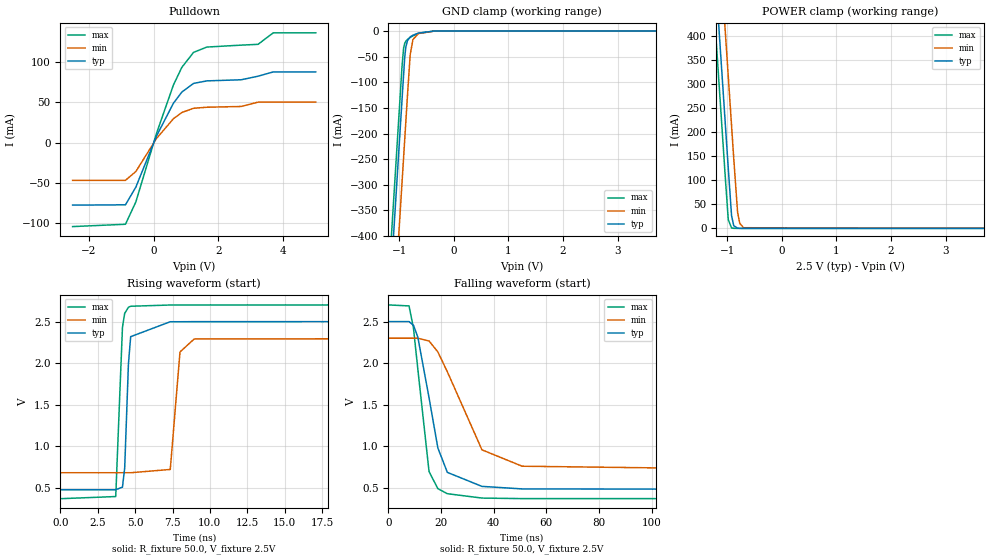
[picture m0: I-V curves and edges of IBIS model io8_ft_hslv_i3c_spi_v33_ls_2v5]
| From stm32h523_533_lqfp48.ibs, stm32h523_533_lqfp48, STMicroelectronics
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[Model]   io8_ft_hslv_i3c_spi_v33_ls_2v5
Model_type I/O_open_drain
Polarity   Non-Inverting
Enable   Active-Low
| CAP_THRESHOLD on pad IOFT is "UDTCAPC" :
| Rising=20.0% of vddiom   Falling=80.0% of vddiom
| C_comp min and max val. don't necessarily correlate with the min and max pvt
| but are the smallest and greatest pad capacitance found.
| var   typ   min   max
C_comp   3.86836pF  3.83545pF  3.96274pF
|C_comp_pulldown   3.86836pF  3.83545pF  3.96274pF
Vinl = 1.15V
Vinh = 1.35V
Vmeas = 1.25V   | Reference voltage for timing measurements
Cref  = 50.0pF   | Timing specification test load capacitance value
Rref  = 1.0MOhm   | Timing specification test load resistance value
Vref  = 1.375V   | Timing specification test load voltage
[Model Spec]
| TIME_THRESHOLD on pin ZII2CV11 is "CMOS" :
| Rising=40.0% of vdd   Falling=60.0% of vdd
Vinl 978.80000mV 906.80000mV 1.05480V
Vinh 1.39920V 1.29220V 1.48720V
| variable   typ   min   max
[Temperature Range] 25.0 125.0 -40.0
| variable   typ   min   max
[Voltage Range] 2.5V 2.3V 2.7V
| variable   typ   min   max
[POWER Clamp Reference] 2.5V 2.3V 2.7V
| variable   typ   min   max
[GND Clamp Reference] 0V 0V 0V
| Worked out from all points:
|   slope of the pulldown table from 0 to 0.375 V, typ, clamps not added: 11.5 ohm
|   GND clamp passes 1 mA (typ) near -0.52 V on its own axis
|   POWER clamp passes 1 mA (typ) near -0.84 V on its own axis
|   rising waveform, R_fixture 50.0, V_fixture 2.5V: 20-80 % time 253ps typ, 304ps min, 242ps max; typ from 0.481 V to 2.5 V
|   falling waveform, R_fixture 50.0, V_fixture 2.5V: 20-80 % time 6.98ns typ, 13.1ns min, 4.56ns max; typ from 2.5 V to 0.481 V
[POWER Clamp]
-2.5V     2.708A     2.899A     2.597A
-1.23V    548.8mA    740.2mA    437.5mA
-1.16V    429.8mA    621.2mA    318.5mA
-1.12V    361.8mA    553.2mA    250.5mA
-1.03V    208.8mA    400.2mA    97.53mA
-980mV    123.8mA    315.2mA    17.95mA
-920mV    26.3mA     213.2mA    906uA
-880mV    5.543mA    145.2mA    123.7uA
-810mV    363.5uA    33.6mA     3.797uA
-770mV    76.62uA    10.47mA    518.8nA
-700mV    5.026uA    1.361mA    16.09nA
5V        0A         0A         0A
[GND Clamp]
-2.5V     -2.77A     -2.931A    -2.704A
-1.21V    -576.8mA   -738.1mA   -511.3mA
-950mV    -134.8mA   -296.1mA   -69.34mA
-920mV    -83.82mA   -245.1mA   -32.48mA
-900mV    -50.56mA   -211.1mA   -24.02mA
-880mV    -31.31mA   -177.1mA   -19.85mA
-850mV    -18.7mA    -126.1mA   -16.34mA
-800mV    -11.46mA   -46.18mA   -12.45mA
-750mV    -8.203mA   -16.63mA   -9.325mA
-650mV    -4.063mA   -4.987mA   -4.427mA
-360mV    -35.05uA   -165.1uA   -9.564uA
5V        7.96nA     1.281uA    294pA
| variable   typ   min   max
[Pullup Reference] 2.5V 2.3V 2.7V
| variable   typ   min   max
[Pulldown Reference] 0V 0V 0V
[Pulldown]
-2.5V     -77.63mA   -46.85mA   -104.3mA
-870mV    -77.24mA   -46.85mA   -101.4mA
-550mV    -55.3mA    -35.88mA   -73.72mA
90mV      8.401mA    5.299mA    11.79mA
610mV     49.03mA    29.75mA    71.69mA
870mV     62.92mA    37.48mA    93.62mA
1.23V     73.63mA    42.72mA    112.2mA
1.64V     76.78mA    44.01mA    118.8mA
2.7V      78.15mA    44.99mA    121.2mA
3.22V     82.58mA    50.35mA    122.2mA
3.69V     87.93mA    50.35mA    136.5mA
5V        87.93mA    50.35mA    136.5mA
[Ramp]
dV/dt_r 1.21163V/248.65431ps 969.22844mV/300.79995ps 1.39627V/238.26042ps
dV/dt_f 1.21165V/6.77947ns 969.25319mV/12.8558ns 1.39628V/4.50807ns
R_load = 50.0
| Removed startup time: 0s 0s 0s  .
| Removed end time: 48.75ns.
[Rising Waveform]
R_fixture   = 50.0
V_fixture   = 2.5V
V_fixture_min = 2.3V
V_fixture_max = 2.7V
0s        480.6mV    684.6mV    372.9mV
3.7ns     480.3mV    684.6mV    398.7mV
4.15ns    511.7mV    684.6mV    2.431V
4.3ns     743.3mV    684.6mV    2.599V
4.55ns    1.992V     684.6mV    2.672V
4.7ns     2.319V     684.6mV    2.684V
7.35ns    2.498V     724.2mV    2.699V
8ns       2.498V     2.135V     2.699V
8.95ns    2.499V     2.291V     2.7V
48.75ns   2.5V       2.3V       2.7V
| Removed startup time: 0s 0s 0s  .
| Removed end time: 248.75ns.
[Falling Waveform]
R_fixture   = 50.0
V_fixture   = 2.5V
V_fixture_min = 2.3V
V_fixture_max = 2.7V
0s        2.5V       2.3V       2.7V
7.85ns    2.5V       2.3V       2.688V
9.55ns    2.455V     2.3V       2.418V
11.2ns    2.312V     2.3V       1.927V
15.45ns   1.586V     2.267V     699mV
18.8ns    982.2mV    2.136V     493.4mV
22.4ns    689mV      1.897V     433mV
35.55ns   520.7mV    959.9mV    380.4mV
50.8ns    490.4mV    763mV      373.9mV
248.8ns   480.6mV    684.6mV    372.9mV
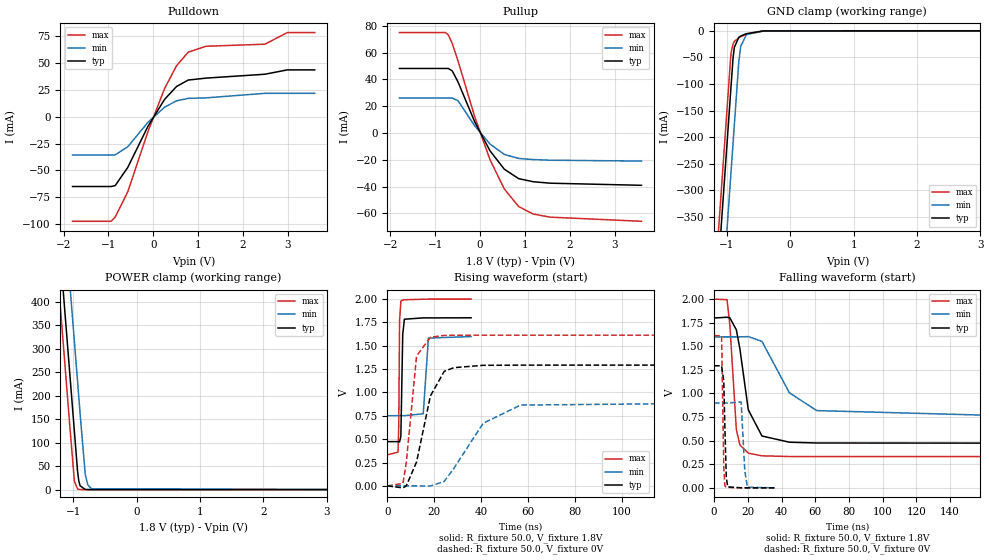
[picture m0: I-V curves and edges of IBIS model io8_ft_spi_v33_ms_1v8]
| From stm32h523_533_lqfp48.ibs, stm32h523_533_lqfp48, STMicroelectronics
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[Model]   io8_ft_spi_v33_ms_1v8
Model_type I/O
Polarity   Non-Inverting
Enable   Active-Low
| CAP_THRESHOLD on pad IOFT is "UDTCAPC" :
| Rising=20.0% of vddiom   Falling=80.0% of vddiom
| C_comp min and max val. don't necessarily correlate with the min and max pvt
| but are the smallest and greatest pad capacitance found.
| var   typ   min   max
C_comp   3.69208pF  3.66965pF  3.86716pF
|C_comp_pullup   2.28990pF  2.21760pF  2.21555pF
|C_comp_pulldown   1.40218pF  1.45205pF  1.65161pF
Vinl = 480.0mV
Vinh = 1.4V
Vmeas = 900.0mV   | Reference voltage for timing measurements
Cref  = 50.0pF   | Timing specification test load capacitance value
Rref  = 100.0MOhm   | Timing specification test load resistance value
Vref  = 900.0mV   | Timing specification test load voltage
[Model Spec]
| TIME_THRESHOLD on pin ZIV33M is "CMOS" :
| Rising=40.0% of vddiom   Falling=60.0% of vddiom
Vinl 693.80000mV 621.80000mV 774.80000mV
Vinh 1.05820V 933.20000mV 1.16320V
| variable   typ   min   max
[Temperature Range] 25.0 125.0 -40.0
| variable   typ   min   max
[Voltage Range] 1.8V 1.6V 2.0V
| variable   typ   min   max
[POWER Clamp Reference] 1.8V 1.6V 2.0V
| variable   typ   min   max
[GND Clamp Reference] 0V 0V 0V
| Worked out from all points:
|   slope of the pulldown table from 0 to 0.27 V, typ, clamps not added: 15.8 ohm
|   slope of the pullup table from 0 to 0.27 V, typ, clamps not added: 17.1 ohm
|   GND clamp passes 1 mA (typ) near -0.52 V on its own axis
|   POWER clamp passes 1 mA (typ) near -0.84 V on its own axis
|   rising waveform, R_fixture 50.0, V_fixture 1.8V: 20-80 % time 414ps typ, 848ps min, 290ps max; typ from 0.474 V to 1.8 V
|   falling waveform, R_fixture 50.0, V_fixture 1.8V: 20-80 % time 7.23ns typ, 16.4ns min, 3.35ns max; typ from 1.8 V to 0.474 V
|   rising waveform, R_fixture 50.0, V_fixture 0V: 20-80 % time 6.85ns typ, 15ns min, 3.49ns max; typ from 0 V to 1.29 V
|   falling waveform, R_fixture 50.0, V_fixture 0V: 20-80 % time 1.1ns typ, 1.58ns min, 753ps max; typ from 1.29 V to 0 V
[POWER Clamp]
-1.8V     1.518A     1.709A     1.407A
-1.23V    548.8mA    740.2mA    437.5mA
-1.16V    429.8mA    621.2mA    318.5mA
-1.05V    242.8mA    434.2mA    131.5mA
-980mV    123.8mA    315.2mA    17.95mA
-930mV    38.81mA    230.2mA    1.49mA
-910mV    17.82mA    196.2mA    550.8uA
-890mV    8.18mA     162.2mA    203.5uA
-810mV    363.5uA    33.6mA     3.797uA
-770mV    76.62uA    10.47mA    518.8nA
-710mV    7.416uA    1.822mA    26.34nA
3.6V      0A         0A         0A
[GND Clamp]
-1.8V     -1.579A    -1.74A     -1.515A
-1.24V    -627.3mA   -788.3mA   -562.7mA
-1.05V    -304.3mA   -465.3mA   -239.7mA
-940mV    -117.3mA   -278.3mA   -52.69mA
-930mV    -100.3mA   -261.3mA   -40.52mA
-900mV    -50.11mA   -210.3mA   -24.23mA
-880mV    -30.95mA   -176.3mA   -20.02mA
-810mV    -12.18mA   -57.97mA   -13.23mA
-780mV    -9.807mA   -29.1mA    -11.19mA
-690mV    -5.41mA    -7.142mA   -6.184mA
-420mV    -170.4uA   -446.1uA   -81.94uA
3.6V      5.755nA    953.4nA    228.2pA
| variable   typ   min   max
[Pullup Reference] 1.8V 1.6V 2.0V
| variable   typ   min   max
[Pulldown Reference] 0V 0V 0V
[Pullup]
-1.8V     48.22mA    26.13mA    75.02mA
-770mV    48.22mA    26.13mA    75.02mA
-710mV    48.22mA    26.13mA    73.25mA
-620mV    46.37mA    26.13mA    66.82mA
-490mV    37.97mA    24.09mA    53.59mA
-120mV    8.372mA    5.391mA    12.2mA
220mV     -13.2mA    -8.17mA    -19.85mA
540mV     -27mA      -15.96mA   -41.75mA
860mV     -34.04mA   -18.97mA   -54.88mA
1.18V     -36.34mA   -19.79mA   -60.45mA
1.56V     -37.44mA   -20.28mA   -62.79mA
3.6V      -39.03mA   -20.93mA   -65.9mA
[Pulldown]
-1.8V     -65.02mA   -35.56mA   -97.42mA
-940mV    -65.02mA   -35.56mA   -97.42mA
-850mV    -64.17mA   -35.56mA   -93.49mA
-570mV    -47.32mA   -28.01mA   -70.04mA
-120mV    -9.088mA   -5.279mA   -14.07mA
250mV     16.04mA    8.832mA    26.05mA
520mV     28.19mA    14.82mA    47.53mA
780mV     34.17mA    17.07mA    60.14mA
1.18V     35.97mA    17.56mA    65.65mA
2.49V     39.57mA    21.77mA    67.55mA
2.99V     43.62mA    21.77mA    78.38mA
3.6V      43.62mA    21.77mA    78.38mA
[Ramp]
dV/dt_r 776.15149mV/6.73951ns 539.49296mV/14.79132ns 968.54289mV/3.48709ns
dV/dt_f 795.78722mV/6.62356ns 508.97361mV/16.22716ns 1.00099V/3.34756ns
R_load = 50.0
| Removed startup time: 0s 0s 0s  .
| Removed end time: 35.75ns.
[Rising Waveform]
R_fixture   = 50.0
V_fixture   = 1.8V
V_fixture_min = 1.6V
V_fixture_max = 2.0V
0s        473.7mV    751.7mV    331.7mV
4.6ns     473.7mV    751.7mV    361.3mV
4.9ns     472.5mV    751.7mV    645.3mV
5.25ns    470.5mV    751.7mV    1.766V
5.8ns     531mV      751.7mV    1.979V
6.6ns     1.624V     751.7mV    1.991V
7.3ns     1.785V     751.7mV    1.993V
15.35ns   1.799V     772mV      1.999V
17.55ns   1.799V     1.583V     2V
35.75ns   1.8V       1.599V     2V
| Removed startup time: 0s 0s 0s  .
| Removed end time: 198.75ns.
[Falling Waveform]
R_fixture   = 50.0
V_fixture   = 1.8V
V_fixture_min = 1.6V
V_fixture_max = 2.0V
0s        1.8V       1.6V       2V
7.7ns     1.808V     1.6V       1.994V
9.4ns     1.8V       1.6V       1.717V
13.2ns    1.675V     1.6V       619.4mV
15.3ns    1.475V     1.6V       455.6mV
20.3ns    827.5mV    1.603V     367.9mV
28.4ns    549.5mV    1.552V     339.5mV
44.65ns   483.9mV    1.008V     332.2mV
60.85ns   475.4mV    818.9mV    331.7mV
198.8ns   473.7mV    751.7mV    331.7mV
| Removed startup time: 0s 0s 0s  .
| Removed end time: 198.6ns.
[Rising Waveform]
R_fixture   = 50.0
V_fixture   = 0V
V_fixture_min = 0V
V_fixture_max = 0V
0s        178.4nV    440.5nV    128.9nV
6.7ns     -21.42mV   449.7nV    26.51mV
8.1ns     -968.5uV   454.4nV    244.7mV
12.5ns    256.2mV    -1.06uV    1.391V
18.4ns    962.8mV    -1.644mV   1.592V
24.3ns    1.227V     47.4mV     1.611V
28.4ns    1.266V     187.6mV    1.613V
40.9ns    1.291V     670.2mV    1.614V
56.8ns    1.293V     864.8mV    1.614V
198.6ns   1.294V     899.2mV    1.614V
| Removed startup time: 0s 0s 0s  .
| Removed end time: 35.75ns.
[Falling Waveform]
R_fixture   = 50.0
V_fixture   = 0V
V_fixture_min = 0V
V_fixture_max = 0V
0s        1.294V     899.3mV    1.614V
4.45ns    1.293V     899.3mV    1.612V
5.75ns    1.134V     899.3mV    218.7mV
6.4ns     642.4mV    899.3mV    21.23mV
7.25ns    117.6mV    899.3mV    5.199mV
8.05ns    10.65mV    899.3mV    4.431mV
16.05ns   846.3uV    909.9mV    359.1uV
18.25ns   570.8uV    174.5mV    248.1uV
19.75ns   461.9uV    7.352mV    194.3uV
35.75ns   73.53uV    645.7uV    14.1uV
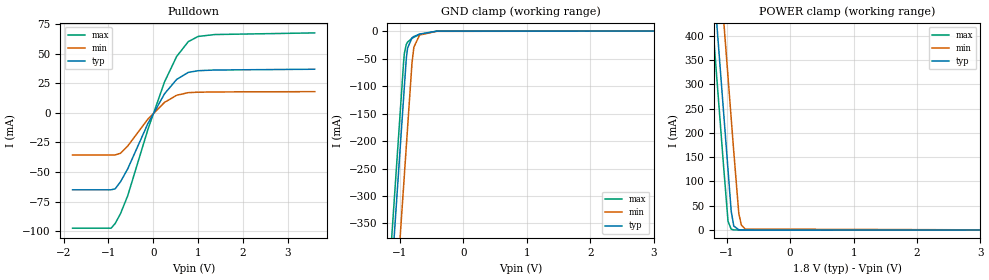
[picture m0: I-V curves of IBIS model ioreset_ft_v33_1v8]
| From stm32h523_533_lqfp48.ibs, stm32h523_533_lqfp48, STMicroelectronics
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[Model]   ioreset_ft_v33_1v8
Model_type I/O_open_drain
Polarity   Inverting
Enable   Active-Low
| CAP_THRESHOLD on pad IOFT is "UDTCAPC" :
| Rising=20.0% of vddiom   Falling=80.0% of vddiom
| C_comp min and max val. don't necessarily correlate with the min and max pvt
| but are the smallest and greatest pad capacitance found.
| var   typ   min   max
C_comp   3.16940pF  3.14035pF  3.18100pF
|C_comp_pulldown   3.16940pF  3.14035pF  3.18100pF
Vinl = 800.0mV
Vinh = 1.0V
Vmeas = 900.0mV   | Reference voltage for timing measurements
Cref  = 50.0pF   | Timing specification test load capacitance value
Rref  = 1.0MOhm   | Timing specification test load resistance value
Vref  = 990.0mV   | Timing specification test load voltage
[Model Spec]
| TIME_THRESHOLD on pin ZIV33M is "CMOS" :
| Rising=40.0% of vddiom   Falling=60.0% of vddiom
Vinl 699.80000mV 627.80000mV 779.80000mV
Vinh 1.05220V 928.20000mV 1.15620V
| variable   typ   min   max
[Temperature Range] 25.0 125.0 -40.0
| variable   typ   min   max
[Voltage Range] 1.8V 1.6V 2.0V
| variable   typ   min   max
[POWER Clamp Reference] 1.8V 1.6V 2.0V
| variable   typ   min   max
[GND Clamp Reference] 0V 0V 0V
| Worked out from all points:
|   slope of the pulldown table from 0 to 0.27 V, typ, clamps not added: 15.8 ohm
|   GND clamp passes 1 mA (typ) near -0.52 V on its own axis
|   POWER clamp passes 1 mA (typ) near -0.84 V on its own axis
[POWER Clamp]
-1.8V     1.518A     1.709A     1.407A
-1.24V    565.8mA    757.2mA    454.5mA
-1.18V    463.8mA    655.2mA    352.5mA
-1.11V    344.8mA    536.2mA    233.5mA
-1.05V    242.8mA    434.2mA    131.5mA
-980mV    123.8mA    315.2mA    17.95mA
-930mV    38.81mA    230.2mA    1.49mA
-890mV    8.18mA     162.2mA    203.5uA
-810mV    363.5uA    33.6mA     3.797uA
-770mV    76.62uA    10.47mA    518.7nA
-710mV    7.416uA    1.822mA    26.23nA
3.6V      0A         0A         0A
[GND Clamp]
-1.8V     -1.579A    -1.74A     -1.515A
-1.24V    -627.3mA   -788.3mA   -562.7mA
-1.05V    -304.3mA   -465.3mA   -239.7mA
-940mV    -117.3mA   -278.3mA   -52.69mA
-930mV    -100.3mA   -261.3mA   -40.52mA
-900mV    -50.11mA   -210.3mA   -24.22mA
-880mV    -30.95mA   -176.3mA   -20.02mA
-810mV    -12.18mA   -57.96mA   -13.22mA
-780mV    -9.803mA   -29.1mA    -11.18mA
-690mV    -5.404mA   -7.14mA    -6.176mA
-420mV    -168.9uA   -443.8uA   -80.87uA
3.6V      312.6pA    43.66nA    94.46pA
| variable   typ   min   max
[Pullup Reference] 1.8V 1.6V 2.0V
| variable   typ   min   max
[Pulldown Reference] 0V 0V 0V
[Pulldown]
-1.8V     -65.01mA   -35.56mA   -97.42mA
-940mV    -65.01mA   -35.56mA   -97.42mA
-850mV    -64.17mA   -35.56mA   -93.5mA
-730mV    -58.19mA   -34.15mA   -85.08mA
-570mV    -47.32mA   -28.01mA   -70.04mA
-120mV    -9.088mA   -5.279mA   -14.07mA
250mV     16.04mA    8.832mA    26.05mA
520mV     28.19mA    14.82mA    47.53mA
780mV     34.17mA    17.07mA    60.14mA
1V        35.61mA    17.44mA    64.53mA
1.37V     36.18mA    17.65mA    66.15mA
3.6V      36.85mA    17.91mA    67.54mA
[Ramp]
dV/dt_r 793.63753mV/454.81899ps 509.89008mV/978.78162ps 1.00535V/290.26081ps
dV/dt_f 795.78722mV/18.98959ns 508.98182mV/47.36521ns 1.00093V/9.59494ns
R_load = 50.0
| Removed startup time: 0s 0s 0s  .
| Removed end time: 99.99us.
|[End]
